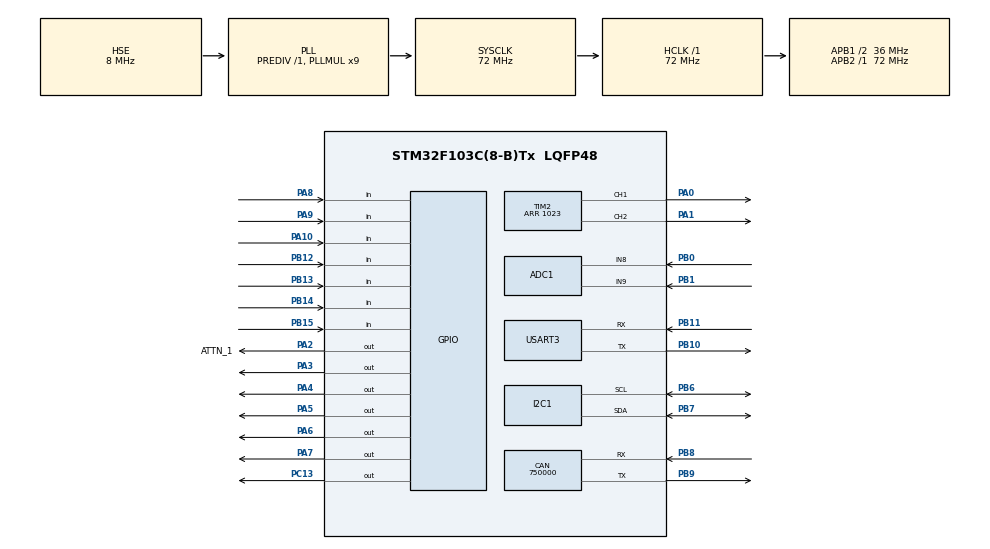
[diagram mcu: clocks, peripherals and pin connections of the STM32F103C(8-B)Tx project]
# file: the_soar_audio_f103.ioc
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ADC1.Channel-0\#ChannelRegularConversion=ADC_CHANNEL_8
ADC1.NbrOfConversionFlag=1
ADC1.Rank-0\#ChannelRegularConversion=1
ADC1.SamplingTime-0\#ChannelRegularConversion=ADC_SAMPLETIME_1CYCLE_5
ADC1.master=1
CAN.CalculateBaudRate=750000
CAN.CalculateTimeBit=1333.33
CAN.CalculateTimeQuantum=444.44444444444446
Dma.Request0=TIM4_CH1
Dma.TIM4_CH1.0.Direction=DMA_MEMORY_TO_PERIPH
Dma.TIM4_CH1.0.Instance=DMA1_Channel1
Dma.TIM4_CH1.0.MemDataAlignment=DMA_MDATAALIGN_WORD
Dma.TIM4_CH1.0.MemInc=DMA_MINC_ENABLE
Dma.TIM4_CH1.0.Mode=DMA_CIRCULAR
Dma.TIM4_CH1.0.PeriphDataAlignment=DMA_PDATAALIGN_WORD
Dma.TIM4_CH1.0.PeriphInc=DMA_PINC_DISABLE
Dma.TIM4_CH1.0.Priority=DMA_PRIORITY_HIGH
FREERTOS.Tasks01=defaultTask,24,128,StartDefaultTask,Default,NULL,Dynamic,NULL,NULL
Mcu.Family=STM32F1
Mcu.Name=STM32F103C(8-B)Tx
Mcu.Package=LQFP48
NVIC.DMA1_Channel1_IRQn=true\:5\:0\:false\:false\:true\:true\:false\:true
NVIC.PriorityGroup=NVIC_PRIORITYGROUP_4
NVIC.TIM1_UP_IRQn=true\:15\:0\:false\:false\:true\:false\:false\:true
NVIC.TimeBase=TIM1_UP_IRQn
NVIC.TimeBaseIP=TIM1
PA0-WKUP.Signal=S_TIM2_CH1_ETR
PA1.Signal=S_TIM2_CH2
PA10.Signal=GPIO_Input
PA13.Mode=Serial_Wire
PA13.Signal=SYS_JTMS-SWDIO
PA14.Mode=Serial_Wire
PA14.Signal=SYS_JTCK-SWCLK
PA2.GPIO_Label=ATTN_1
PA2.GPIO_ModeDefaultOutputPP=GPIO_MODE_OUTPUT_OD
PA2.Signal=GPIO_Output
PA3.GPIO_ModeDefaultOutputPP=GPIO_MODE_OUTPUT_OD
PA3.Signal=GPIO_Output
PA4.GPIO_ModeDefaultOutputPP=GPIO_MODE_OUTPUT_OD
PA4.GPIO_Speed=GPIO_SPEED_FREQ_LOW
PA4.Signal=GPIO_Output
PA5.GPIO_ModeDefaultOutputPP=GPIO_MODE_OUTPUT_OD
PA5.Signal=GPIO_Output
PA6.GPIO_ModeDefaultOutputPP=GPIO_MODE_OUTPUT_OD
PA6.Signal=GPIO_Output
PA7.GPIO_ModeDefaultOutputPP=GPIO_MODE_OUTPUT_OD
PA7.Signal=GPIO_Output
PA8.Signal=GPIO_Input
PA9.Signal=GPIO_Input
PB0.Signal=ADCx_IN8
PB1.Signal=ADCx_IN9
PB10.Mode=Asynchronous
PB10.Signal=USART3_TX
PB11.Mode=Asynchronous
PB11.Signal=USART3_RX
PB12.Signal=GPIO_Input
PB13.Signal=GPIO_Input
PB14.Signal=GPIO_Input
PB15.Signal=GPIO_Input
PB6.Mode=I2C
PB6.Signal=I2C1_SCL
PB7.Mode=I2C
PB7.Signal=I2C1_SDA
PB8.Mode=CAN_Activate
PB8.Signal=CAN_RX
PB9.Mode=CAN_Activate
PB9.Signal=CAN_TX
PC13-TAMPER-RTC.Signal=GPIO_Output
PC14-OSC32_IN.Mode=LSE-External-Oscillator
PC14-OSC32_IN.Signal=RCC_OSC32_IN
PC15-OSC32_OUT.Mode=LSE-External-Oscillator
PC15-OSC32_OUT.Signal=RCC_OSC32_OUT
PD0-OSC_IN.Mode=HSE-External-Oscillator
PD0-OSC_IN.Signal=RCC_OSC_IN
PD1-OSC_OUT.Mode=HSE-External-Oscillator
PD1-OSC_OUT.Signal=RCC_OSC_OUT
ProjectManager.HeapSize=0x200
ProjectManager.StackSize=0x400
ProjectManager.TargetToolchain=STM32CubeIDE
RCC.ADCPresc=RCC_ADCPCLK2_DIV6
RCC.AHBFreq_Value=72000000
RCC.APB1CLKDivider=RCC_HCLK_DIV2
RCC.APB1Freq_Value=36000000
RCC.APB1TimFreq_Value=72000000
RCC.APB2Freq_Value=72000000
RCC.APB2TimFreq_Value=72000000
RCC.HCLKFreq_Value=72000000
RCC.PLLMUL=RCC_PLL_MUL9
RCC.PLLSourceVirtual=RCC_PLLSOURCE_HSE
RCC.SYSCLKFreq_VALUE=72000000
RCC.SYSCLKSource=RCC_SYSCLKSOURCE_PLLCLK
RCC.USBFreq_Value=72000000
SH.ADCx_IN8.0=ADC1_IN8,IN8
SH.ADCx_IN9.0=ADC1_IN9,IN9
SH.S_TIM2_CH1_ETR.0=TIM2_CH1,PWM Generation1 CH1
SH.S_TIM2_CH2.0=TIM2_CH2,PWM Generation2 CH2
TIM2.AutoReloadPreload=TIM_AUTORELOAD_PRELOAD_ENABLE
TIM2.Channel-PWM\ Generation1\ CH1=TIM_CHANNEL_1
TIM2.Channel-PWM\ Generation2\ CH2=TIM_CHANNEL_2
TIM2.Period=1023
TIM2.Pulse-PWM\ Generation1\ CH1=100
TIM2.TIM_MasterOutputTrigger=TIM_TRGO_RESET
TIM4.AutoReloadPreload=TIM_AUTORELOAD_PRELOAD_ENABLE
TIM4.Channel-Output\ Compare1\ No\ Output=TIM_CHANNEL_1
TIM4.Period=100
USART3.VirtualMode=VM_ASYNC
VP_FREERTOS_VS_CMSIS_V2.Mode=CMSIS_V2
VP_SYS_VS_tim1.Mode=TIM1
VP_TIM4_VS_no_output1.Mode=Output Compare1 No Output
board=custom

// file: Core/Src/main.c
/* USER CODE BEGIN Header */
/**
  ******************************************************************************
  * @file           : main.c
  * @brief          : Main program body
  ******************************************************************************
  * @attention
  *
  * <h2><center>&copy; Copyright (c) 2022 STMicroelectronics.
  * All rights reserved.</center></h2>
  *
  * This software component is licensed by ST under BSD 3-Clause license,
  * the "License"; You may not use this file except in compliance with the
  * License. You may obtain a copy of the License at:
  *                        opensource.org/licenses/BSD-3-Clause
  *
  ******************************************************************************
  */
/* USER CODE END Header */
#include "main.h"
#include "cmsis_os.h"

/* USER CODE BEGIN Includes */
#include "audio.h"
/* USER CODE END Includes */

ADC_HandleTypeDef hadc1;

CAN_HandleTypeDef hcan;

I2C_HandleTypeDef hi2c1;

TIM_HandleTypeDef htim2;
TIM_HandleTypeDef htim4;
DMA_HandleTypeDef hdma_tim4_ch1;
DMA_HandleTypeDef hdma_tim4_ch2;

UART_HandleTypeDef huart3;

/* Definitions for defaultTask */
osThreadId_t defaultTaskHandle;
const osThreadAttr_t defaultTask_attributes = {
  .name = "defaultTask",
  .stack_size = 128 * 4,
  .priority = (osPriority_t) osPriorityNormal,
};
/* USER CODE BEGIN PV */
osThreadId_t audioTaskHandle;
/* USER CODE END PV */

void SystemClock_Config(void);
static void MX_GPIO_Init(void);
static void MX_ADC1_Init(void);
static void MX_CAN_Init(void);
static void MX_I2C1_Init(void);
static void MX_TIM2_Init(void);
static void MX_DMA_Init(void);
static void MX_TIM4_Init(void);
static void MX_USART3_UART_Init(void);
void StartDefaultTask(void *argument);

int main(void)
{

  /* MCU Configuration--------------------------------------------------------*/

  /* Reset of all peripherals, Initializes the Flash interface and the Systick. */
  HAL_Init();

  /* Configure the system clock */
  SystemClock_Config();

  /* Initialize all configured peripherals */
  MX_GPIO_Init();
  MX_ADC1_Init();
  MX_CAN_Init();
  MX_I2C1_Init();
  MX_TIM2_Init();
  MX_DMA_Init();
  MX_TIM4_Init();
  MX_USART3_UART_Init();

  /* Init scheduler */
  osKernelInitialize();

  /* Create the thread(s) */
  /* creation of defaultTask */
  defaultTaskHandle = osThreadNew(StartDefaultTask, NULL, &defaultTask_attributes);

  /* USER CODE BEGIN RTOS_THREADS */
  /* add threads, ... */
  audioTaskHandle = osThreadNew(StartAudioTask, NULL,  &defaultTask_attributes);
  /* USER CODE END RTOS_THREADS */

  /* Start scheduler */
  osKernelStart();

  /* We should never get here as control is now taken by the scheduler */
  /* Infinite loop */
  while (1)
  {

  }
}

void SystemClock_Config(void)
{
  RCC_OscInitTypeDef RCC_OscInitStruct = {0};
  RCC_ClkInitTypeDef RCC_ClkInitStruct = {0};
  RCC_PeriphCLKInitTypeDef PeriphClkInit = {0};

  /** Initializes the RCC Oscillators according to the specified parameters
  * in the RCC_OscInitTypeDef structure.
  */
  RCC_OscInitStruct.OscillatorType = RCC_OSCILLATORTYPE_HSE;
  RCC_OscInitStruct.HSEState = RCC_HSE_ON;
  RCC_OscInitStruct.HSEPredivValue = RCC_HSE_PREDIV_DIV1;
  RCC_OscInitStruct.HSIState = RCC_HSI_ON;
  RCC_OscInitStruct.PLL.PLLState = RCC_PLL_ON;
  RCC_OscInitStruct.PLL.PLLSource = RCC_PLLSOURCE_HSE;
  RCC_OscInitStruct.PLL.PLLMUL = RCC_PLL_MUL9;
  if (HAL_RCC_OscConfig(&RCC_OscInitStruct) != HAL_OK)
  {
    Error_Handler();
  }
  /** Initializes the CPU, AHB and APB buses clocks
  */
  RCC_ClkInitStruct.ClockType = RCC_CLOCKTYPE_HCLK|RCC_CLOCKTYPE_SYSCLK
                              |RCC_CLOCKTYPE_PCLK1|RCC_CLOCKTYPE_PCLK2;
  RCC_ClkInitStruct.SYSCLKSource = RCC_SYSCLKSOURCE_PLLCLK;
  RCC_ClkInitStruct.AHBCLKDivider = RCC_SYSCLK_DIV1;
  RCC_ClkInitStruct.APB1CLKDivider = RCC_HCLK_DIV2;
  RCC_ClkInitStruct.APB2CLKDivider = RCC_HCLK_DIV1;

  if (HAL_RCC_ClockConfig(&RCC_ClkInitStruct, FLASH_LATENCY_2) != HAL_OK)
  {
    Error_Handler();
  }
  PeriphClkInit.PeriphClockSelection = RCC_PERIPHCLK_ADC;
  PeriphClkInit.AdcClockSelection = RCC_ADCPCLK2_DIV6;
  if (HAL_RCCEx_PeriphCLKConfig(&PeriphClkInit) != HAL_OK)
  {
    Error_Handler();
  }
}

static void MX_ADC1_Init(void)
{

  ADC_ChannelConfTypeDef sConfig = {0};

  /** Common config
  */
  hadc1.Instance = ADC1;
  hadc1.Init.ScanConvMode = ADC_SCAN_DISABLE;
  hadc1.Init.ContinuousConvMode = DISABLE;
  hadc1.Init.DiscontinuousConvMode = DISABLE;
  hadc1.Init.ExternalTrigConv = ADC_SOFTWARE_START;
  hadc1.Init.DataAlign = ADC_DATAALIGN_RIGHT;
  hadc1.Init.NbrOfConversion = 1;
  if (HAL_ADC_Init(&hadc1) != HAL_OK)
  {
    Error_Handler();
  }
  /** Configure Regular Channel
  */
  sConfig.Channel = ADC_CHANNEL_8;
  sConfig.Rank = ADC_REGULAR_RANK_1;
  sConfig.SamplingTime = ADC_SAMPLETIME_1CYCLE_5;
  if (HAL_ADC_ConfigChannel(&hadc1, &sConfig) != HAL_OK)
  {
    Error_Handler();
  }

}

static void MX_CAN_Init(void)
{

  hcan.Instance = CAN1;
  hcan.Init.Prescaler = 16;
  hcan.Init.Mode = CAN_MODE_NORMAL;
  hcan.Init.SyncJumpWidth = CAN_SJW_1TQ;
  hcan.Init.TimeSeg1 = CAN_BS1_1TQ;
  hcan.Init.TimeSeg2 = CAN_BS2_1TQ;
  hcan.Init.TimeTriggeredMode = DISABLE;
  hcan.Init.AutoBusOff = DISABLE;
  hcan.Init.AutoWakeUp = DISABLE;
  hcan.Init.AutoRetransmission = DISABLE;
  hcan.Init.ReceiveFifoLocked = DISABLE;
  hcan.Init.TransmitFifoPriority = DISABLE;
  if (HAL_CAN_Init(&hcan) != HAL_OK)
  {
    Error_Handler();
  }

}

static void MX_I2C1_Init(void)
{

  hi2c1.Instance = I2C1;
  hi2c1.Init.ClockSpeed = 100000;
  hi2c1.Init.DutyCycle = I2C_DUTYCYCLE_2;
  hi2c1.Init.OwnAddress1 = 0;
  hi2c1.Init.AddressingMode = I2C_ADDRESSINGMODE_7BIT;
  hi2c1.Init.DualAddressMode = I2C_DUALADDRESS_DISABLE;
  hi2c1.Init.OwnAddress2 = 0;
  hi2c1.Init.GeneralCallMode = I2C_GENERALCALL_DISABLE;
  hi2c1.Init.NoStretchMode = I2C_NOSTRETCH_DISABLE;
  if (HAL_I2C_Init(&hi2c1) != HAL_OK)
  {
    Error_Handler();
  }

}

static void MX_TIM2_Init(void)
{

  TIM_MasterConfigTypeDef sMasterConfig = {0};
  TIM_OC_InitTypeDef sConfigOC = {0};

  htim2.Instance = TIM2;
  htim2.Init.Prescaler = 0;
  htim2.Init.CounterMode = TIM_COUNTERMODE_UP;
  htim2.Init.Period = 1023;
  htim2.Init.ClockDivision = TIM_CLOCKDIVISION_DIV1;
  htim2.Init.AutoReloadPreload = TIM_AUTORELOAD_PRELOAD_ENABLE;
  if (HAL_TIM_PWM_Init(&htim2) != HAL_OK)
  {
    Error_Handler();
  }
  sMasterConfig.MasterOutputTrigger = TIM_TRGO_RESET;
  sMasterConfig.MasterSlaveMode = TIM_MASTERSLAVEMODE_DISABLE;
  if (HAL_TIMEx_MasterConfigSynchronization(&htim2, &sMasterConfig) != HAL_OK)
  {
    Error_Handler();
  }
  sConfigOC.OCMode = TIM_OCMODE_PWM1;
  sConfigOC.Pulse = 100;
  sConfigOC.OCPolarity = TIM_OCPOLARITY_HIGH;
  sConfigOC.OCFastMode = TIM_OCFAST_DISABLE;
  if (HAL_TIM_PWM_ConfigChannel(&htim2, &sConfigOC, TIM_CHANNEL_1) != HAL_OK)
  {
    Error_Handler();
  }
  sConfigOC.Pulse = 0;
  if (HAL_TIM_PWM_ConfigChannel(&htim2, &sConfigOC, TIM_CHANNEL_2) != HAL_OK)
  {
    Error_Handler();
  }
  HAL_TIM_MspPostInit(&htim2);

}

static void MX_TIM4_Init(void)
{

  TIM_MasterConfigTypeDef sMasterConfig = {0};
  TIM_OC_InitTypeDef sConfigOC = {0};

  htim4.Instance = TIM4;
  htim4.Init.Prescaler = 0;
  htim4.Init.CounterMode = TIM_COUNTERMODE_UP;
  htim4.Init.Period = 100;
  htim4.Init.ClockDivision = TIM_CLOCKDIVISION_DIV1;
  htim4.Init.AutoReloadPreload = TIM_AUTORELOAD_PRELOAD_ENABLE;
  if (HAL_TIM_OC_Init(&htim4) != HAL_OK)
  {
    Error_Handler();
  }
  sMasterConfig.MasterOutputTrigger = TIM_TRGO_RESET;
  sMasterConfig.MasterSlaveMode = TIM_MASTERSLAVEMODE_DISABLE;
  if (HAL_TIMEx_MasterConfigSynchronization(&htim4, &sMasterConfig) != HAL_OK)
  {
    Error_Handler();
  }
  sConfigOC.OCMode = TIM_OCMODE_TIMING;
  sConfigOC.Pulse = 0;
  sConfigOC.OCPolarity = TIM_OCPOLARITY_HIGH;
  sConfigOC.OCFastMode = TIM_OCFAST_DISABLE;
  if (HAL_TIM_OC_ConfigChannel(&htim4, &sConfigOC, TIM_CHANNEL_1) != HAL_OK)
  {
    Error_Handler();
  }
  if (HAL_TIM_OC_ConfigChannel(&htim4, &sConfigOC, TIM_CHANNEL_2) != HAL_OK)
  {
    Error_Handler();
  }

}

static void MX_USART3_UART_Init(void)
{

  huart3.Instance = USART3;
  huart3.Init.BaudRate = 115200;
  huart3.Init.WordLength = UART_WORDLENGTH_8B;
  huart3.Init.StopBits = UART_STOPBITS_1;
  huart3.Init.Parity = UART_PARITY_NONE;
  huart3.Init.Mode = UART_MODE_TX_RX;
  huart3.Init.HwFlowCtl = UART_HWCONTROL_NONE;
  huart3.Init.OverSampling = UART_OVERSAMPLING_16;
  if (HAL_UART_Init(&huart3) != HAL_OK)
  {
    Error_Handler();
  }

}

static void MX_DMA_Init(void)
{

  /* DMA controller clock enable */
  __HAL_RCC_DMA1_CLK_ENABLE();

  /* DMA interrupt init */
  /* DMA1_Channel1_IRQn interrupt configuration */
  HAL_NVIC_SetPriority(DMA1_Channel1_IRQn, 5, 0);
  HAL_NVIC_EnableIRQ(DMA1_Channel1_IRQn);
  /* DMA1_Channel4_IRQn interrupt configuration */
  HAL_NVIC_SetPriority(DMA1_Channel4_IRQn, 5, 0);
  HAL_NVIC_EnableIRQ(DMA1_Channel4_IRQn);

}

static void MX_GPIO_Init(void)
{
  GPIO_InitTypeDef GPIO_InitStruct = {0};

  /* GPIO Ports Clock Enable */
  __HAL_RCC_GPIOC_CLK_ENABLE();
  __HAL_RCC_GPIOD_CLK_ENABLE();
  __HAL_RCC_GPIOA_CLK_ENABLE();
  __HAL_RCC_GPIOB_CLK_ENABLE();

  /*Configure GPIO pin Output Level */
  HAL_GPIO_WritePin(GPIOC, GPIO_PIN_13, GPIO_PIN_RESET);

  /*Configure GPIO pin Output Level */
  HAL_GPIO_WritePin(GPIOA, ATTN_1_Pin|ATTN_2_Pin|ATTN_3_Pin|ATTN_4_Pin
                          |ATTN_5_Pin|ATTN_6_Pin, GPIO_PIN_RESET);

  /*Configure GPIO pin : PC13 */
  GPIO_InitStruct.Pin = GPIO_PIN_13;
  GPIO_InitStruct.Mode = GPIO_MODE_OUTPUT_PP;
  GPIO_InitStruct.Pull = GPIO_NOPULL;
  GPIO_InitStruct.Speed = GPIO_SPEED_FREQ_LOW;
  HAL_GPIO_Init(GPIOC, &GPIO_InitStruct);

  /*Configure GPIO pins : ATTN_1_Pin ATTN_2_Pin ATTN_3_Pin ATTN_4_Pin
                           ATTN_5_Pin ATTN_6_Pin */
  GPIO_InitStruct.Pin = ATTN_1_Pin|ATTN_2_Pin|ATTN_3_Pin|ATTN_4_Pin
                          |ATTN_5_Pin|ATTN_6_Pin;
  GPIO_InitStruct.Mode = GPIO_MODE_OUTPUT_OD;
  GPIO_InitStruct.Pull = GPIO_NOPULL;
  GPIO_InitStruct.Speed = GPIO_SPEED_FREQ_LOW;
  HAL_GPIO_Init(GPIOA, &GPIO_InitStruct);

  /*Configure GPIO pins : PB12 PB13 PB14 PB15 */
  GPIO_InitStruct.Pin = GPIO_PIN_12|GPIO_PIN_13|GPIO_PIN_14|GPIO_PIN_15;
  GPIO_InitStruct.Mode = GPIO_MODE_INPUT;
  GPIO_InitStruct.Pull = GPIO_NOPULL;
  HAL_GPIO_Init(GPIOB, &GPIO_InitStruct);

  /*Configure GPIO pins : PA8 PA9 PA10 */
  GPIO_InitStruct.Pin = GPIO_PIN_8|GPIO_PIN_9|GPIO_PIN_10;
  GPIO_InitStruct.Mode = GPIO_MODE_INPUT;
  GPIO_InitStruct.Pull = GPIO_NOPULL;
  HAL_GPIO_Init(GPIOA, &GPIO_InitStruct);

}

void StartDefaultTask(void *argument)
{
  for(;;)
  {
    osDelay(1);
  }
}

void HAL_TIM_PeriodElapsedCallback(TIM_HandleTypeDef *htim)
{
  if (htim->Instance == TIM1) {
    HAL_IncTick();
  }
}

void Error_Handler(void)
{
  __disable_irq();
  while (1)
  {
  }
}

/************************ (C) COPYRIGHT STMicroelectronics *****END OF FILE****/
